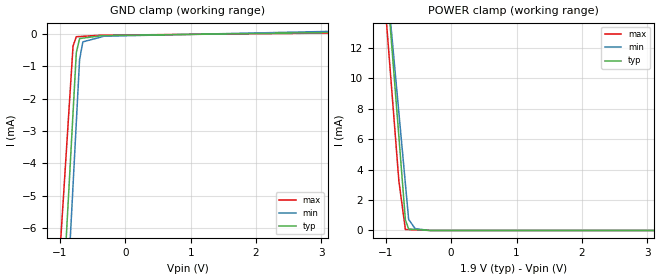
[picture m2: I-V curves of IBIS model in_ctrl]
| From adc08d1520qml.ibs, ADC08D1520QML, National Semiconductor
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[Model] in_ctrl
Model_type Input
Vinl = 290.000mV
Vinh = 1.62000V
C_comp 728.000fF 728.000fF 728.000fF
| variable typ   min   max
[Voltage Range] 1.90000V 1.80000V 2.00000V
[POWER Clamp Reference] 1.90000V 1.80000V 2.00000V
[GND Clamp Reference] 0.00000V 0.00000V 0.00000V
[Temperature Range]   25   125   -55
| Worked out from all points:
|   GND clamp passes 1 mA (typ) near -0.76 V on its own axis
|   POWER clamp passes 1 mA (typ) near -0.71 V on its own axis
[GND Clamp]
-1.9V     -43.35mA   -47.46mA   -35.36mA
-800mV    -2.438mA   -4.68mA    -372uA
-750mV    -578.7uA   -2.736mA   -84.06uA
-700mV    -141uA     -791.2uA   -77.75uA
-650mV    -127.8uA   -243.3uA   -71.45uA
-375mV    -55.38uA   -94.72uA   -36.78uA
-350mV    -48.8uA    -81.21uA   -36.31uA
-325mV    -48.11uA   -67.7uA    -35.83uA
3.8V      65.47uA    110.4uA    42.56uA
[POWER Clamp]
-1.9V     66.56mA    59.39mA    63.83mA
-850mV    8.932mA    10.11mA    6.015mA
-800mV    6.188mA    7.764mA    3.262mA
-700mV    699.4uA    3.071mA    65.53uA
-650mV    99.48uA    723.9uA    57.34uA
-550mV    68.87uA    120.1uA    40.96uA
-500mV    53.57uA    90.09uA    32.77uA
-400mV    22.96uA    38.61uA    16.38uA
-325mV    0A         0A         4.096uA
-250mV    0A         0A         0A
3.8V      0A         0A         0A
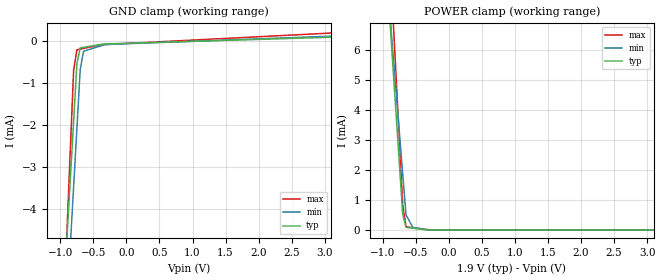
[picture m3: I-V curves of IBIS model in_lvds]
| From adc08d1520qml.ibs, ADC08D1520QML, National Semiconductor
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[Model] in_lvds
Model_type Input
Vinl = 1.05000V
Vinh = 1.45000V
C_comp 545.000fF 545.000fF 545.000fF
| variable typ   min   max
[Voltage Range] 1.90000V 1.80000V 2.00000V
[POWER Clamp Reference] 1.90000V 1.80000V 2.00000V
[GND Clamp Reference] 0.00000V 0.00000V 0.00000V
[Temperature Range]   25   125   -55
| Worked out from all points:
|   GND clamp passes 1 mA (typ) near -0.77 V on its own axis
|   POWER clamp passes 1 mA (typ) near -0.71 V on its own axis
[GND Clamp]
-1.9V     -32.16mA   -34.19mA   -42.34mA
-800mV    -1.905mA   -3.466mA   -691.5uA
-750mV    -529.7uA   -2.069mA   -202.7uA
-700mV    -158.6uA   -673uA     -186.6uA
-650mV    -145.3uA   -238.1uA   -170.5uA
-375mV    -72.14uA   -103.1uA   -82.04uA
-350mV    -65.5uA    -90.84uA   -80.04uA
-325mV    -64.32uA   -78.57uA   -78.04uA
3.8V      129.6uA    163uA      252uA
[POWER Clamp]
-1.9V     40.51mA    34.66mA    51.97mA
-800mV    3.852mA    4.603mA    5.099mA
-750mV    2.186mA    3.236mA    2.969mA
-700mV    519.5uA    1.87mA     838.7uA
-650mV    87.37uA    503.6uA    107.3uA
-550mV    60.48uA    94.98uA    78.66uA
-500mV    47.04uA    71.23uA    64.36uA
-375mV    13.44uA    20.35uA    28.6uA
-325mV    0A         0A         14.3uA
-250mV    0A         0A         0A
3.8V      0A         0A         0A
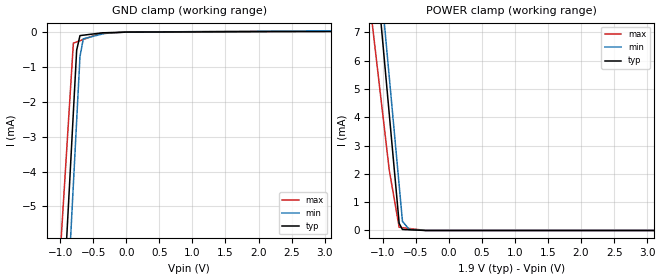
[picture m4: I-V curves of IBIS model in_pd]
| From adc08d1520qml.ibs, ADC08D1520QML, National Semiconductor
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[Model] in_pd
Model_type Input
Vinl = 290.000mV
Vinh = 1.62000V
C_comp 565.000fF 565.000fF 565.000fF
| variable typ   min   max
[Voltage Range] 1.90000V 1.80000V 2.00000V
[POWER Clamp Reference] 1.90000V 1.80000V 2.00000V
[GND Clamp Reference] 0.00000V 0.00000V 0.00000V
[Temperature Range]   25   125   -55
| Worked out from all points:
|   GND clamp passes 1 mA (typ) near -0.76 V on its own axis
|   POWER clamp passes 1 mA (typ) near -0.78 V on its own axis
[GND Clamp]
-1.9V     -41.65mA   -44.77mA   -33.77mA
-800mV    -2.308mA   -4.377mA   -317.7uA
-750mV    -520.3uA   -2.541mA   -282.8uA
-700mV    -101.1uA   -705.2uA   -247.9uA
-650mV    -89.44uA   -193.9uA   -213.1uA
-400mV    -31.13uA   -73.41uA   -38.71uA
-350mV    -19.47uA   -49.31uA   -37.78uA
-325mV    -19.23uA   -37.25uA   -37.31uA
0V        0A         0A         0A
3.8V      19.26uA    44.68uA    39.79uA
[POWER Clamp]
-1.9V     29.93mA    30.99mA    22.25mA
-900mV    4.125mA    5.435mA    2.138mA
-750mV    253.7uA    1.601mA    113.2uA
-700mV    34.22uA    322.9uA    99.04uA
-600mV    24.44uA    40.76uA    70.75uA
-550mV    19.55uA    31.7uA     56.6uA
-450mV    9.777uA    15.85uA    28.3uA
-350mV    0A         0A         0A
-275mV    0A         0A         0A
0V        0A         0A         0A
3.8V      0A         0A         0A
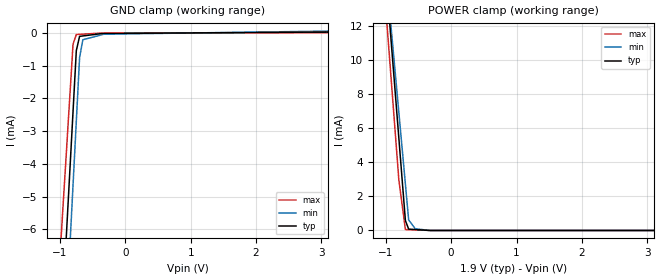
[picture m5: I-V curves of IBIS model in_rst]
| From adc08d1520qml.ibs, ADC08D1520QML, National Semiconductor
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[Model] in_rst
Model_type Input
Vinl = 290.000mV
Vinh = 1.62000V
C_comp 1.11000pF 1.11000pF 1.11000pF
| variable typ   min   max
[Voltage Range] 1.90000V 1.80000V 2.00000V
[POWER Clamp Reference] 1.90000V 1.80000V 2.00000V
[GND Clamp Reference] 0.00000V 0.00000V 0.00000V
[Temperature Range]   25   125   -55
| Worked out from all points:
|   GND clamp passes 1 mA (typ) near -0.76 V on its own axis
|   POWER clamp passes 1 mA (typ) near -0.71 V on its own axis
[GND Clamp]
-1.9V     -43.15mA   -47.34mA   -35.89mA
-800mV    -2.396mA   -4.641mA   -344.6uA
-750mV    -543.9uA   -2.7mA     -50.98uA
-700mV    -106.7uA   -758.5uA   -45.16uA
-650mV    -94.21uA   -210.5uA   -39.34uA
-375mV    -25.52uA   -65.93uA   -7.317uA
-350mV    -19.28uA   -52.79uA   -7.221uA
-325mV    -18.95uA   -39.64uA   -7.124uA
3.8V      34.33uA    72.29uA    8.808uA
[POWER Clamp]
-1.9V     58.54mA    53.14mA    58.28mA
-850mV    7.827mA    9.024mA    5.474mA
-800mV    5.413mA    6.923mA    2.959mA
-700mV    583.1uA    2.722mA    55.5uA
-650mV    79.8uA     621.5uA    48.57uA
-550mV    55.25uA    101.9uA    34.69uA
-500mV    42.97uA    76.46uA    27.75uA
-400mV    18.42uA    32.77uA    13.88uA
-325mV    0A         0A         3.469uA
-250mV    0A         0A         0A
3.8V      0A         0A         0A
